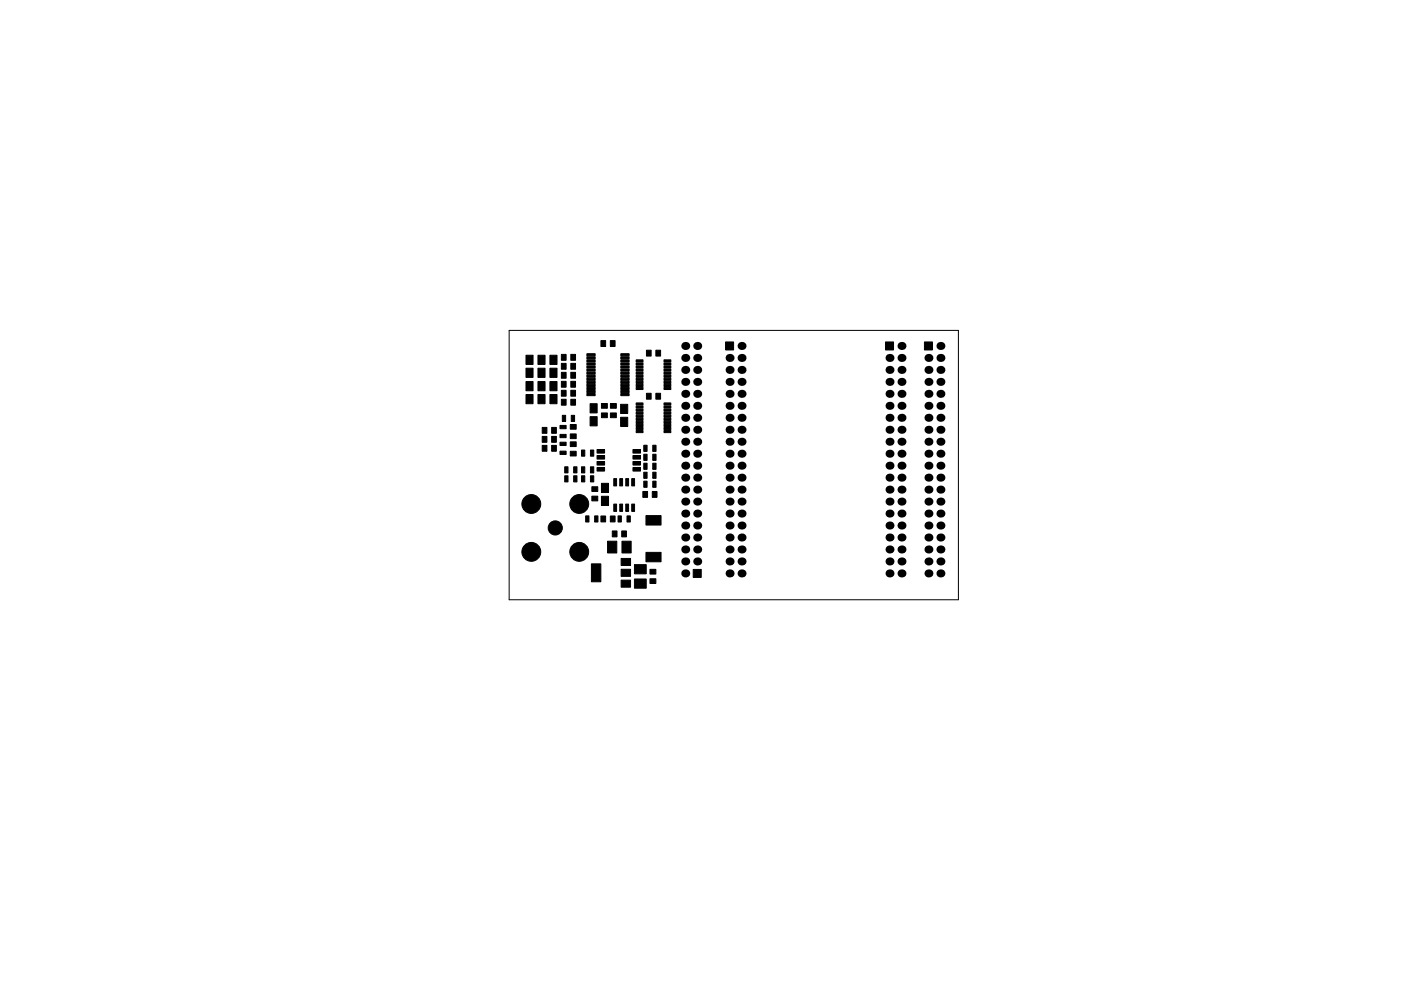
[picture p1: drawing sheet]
<svg xmlns="http://www.w3.org/2000/svg" width="297mm" height="210mm" viewBox="0 0 297 210" stroke-linecap="round" stroke-linejoin="round" font-family="sans-serif">
<path d="M107.9 70.1h95.3v57.1h-95.3z" fill="none" stroke="#000" stroke-width=".21"/>
<g fill="#000" stroke="#000" stroke-width=".21">
<path d="M111.5 75.4h1.5v1.9h-1.5zM111.5 78.1h1.5v2h-1.5zM114.1 75.4h1.5v1.9h-1.5zM114.1 78.1h1.5v2h-1.5zM116.6 75.4h1.5v1.9h-1.5zM116.6 78.1h1.5v2h-1.5zM119 79h1v1.2h-1zM119 77.1h1v1.2h-1zM119 75.2h1v1.2h-1zM121 79h1v1.2h-1zM121 77.1h1v1.2h-1zM121 75.2h1v1.2h-1z"/>
<path d="M124.4 75h1.8v.5h-1.8zM124.4 75.7h1.8v.4h-1.8zM124.4 76.3h1.8v.5h-1.8zM124.4 77h1.8v.4h-1.8zM124.4 77.6h1.8v.5h-1.8zM124.4 78.3h1.8v.4h-1.8zM124.4 78.9h1.8v.5h-1.8zM124.4 79.6h1.8v.4h-1.8zM127.4 72.3h1v1.2h-1zM129.4 72.3h1v1.2h-1zM131.6 79.6h1.8v.4h-1.8zM131.6 78.9h1.8v.5h-1.8z"/>
<path d="M131.6 78.3h1.8v.4h-1.8zM131.6 77.6h1.8v.5h-1.8zM131.6 77h1.8v.4h-1.8zM131.6 76.3h1.8v.5h-1.8zM131.6 75.7h1.8v.4h-1.8zM131.6 75h1.8v.5h-1.8zM134.9 76.3h1.4v.5h-1.4zM134.9 77h1.4v.4h-1.4zM134.9 77.6h1.4v.5h-1.4zM134.9 78.3h1.4v.4h-1.4zM134.9 78.9h1.4v.5h-1.4zM137.1 74.3h1v1.2h-1z"/>
<path d="M139.1 74.3h1v1.2h-1zM140.8 78.9h1.4v.5h-1.4zM140.8 78.3h1.4v.4h-1.4zM140.8 77.6h1.4v.5h-1.4zM140.8 77h1.4v.4h-1.4zM140.8 76.3h1.4v.5h-1.4zM153.8 72.6h1.7v1.7h-1.7zM187.7 72.6h1.7v1.7h-1.7zM196 72.6h1.7v1.7h-1.7zM111.5 81h1.5v1.9h-1.5zM111.5 83.7h1.5v2h-1.5zM114.1 81h1.5v1.9h-1.5z"/>
<path d="M114.1 83.7h1.5v2h-1.5zM115 94.5h1v1.2h-1zM115 92.6h1v1.2h-1zM115 90.7h1v1.2h-1zM116.6 81h1.5v1.9h-1.5zM116.6 83.7h1.5v2h-1.5zM117 94.5h1v1.2h-1zM117 92.6h1v1.2h-1zM117 90.7h1v1.2h-1zM118.7 93.8h1.3v.7h-1.3zM118.7 95.7h1.3v.7h-1.3zM118.7 90.3h1.3v.7h-1.3z"/>
<path d="M118.7 92.2h1.3v.7h-1.3zM119.2 88.1h.7v1.3h-.7zM119 84.7h1v1.3h-1zM119 80.9h1v1.3h-1zM119 82.8h1v1.3h-1zM119.7 99h.7v1.3h-.7zM121.1 88.1h.7v1.3h-.7zM121 84.7h1v1.3h-1zM121 80.9h1v1.3h-1zM121 82.8h1v1.3h-1zM120.9 95.7h1.3v1h-1.3zM120.9 93.7h1.3v1h-1.3z"/>
<path d="M120.9 92.1h1.3v1h-1.3zM120.9 90.1h1.3v1h-1.3zM121.6 99h.7v1.3h-.7zM123.3 95.5h.7v1.3h-.7zM125.1 85.7h1.5v1.9h-1.5zM125.1 88.4h1.5v2h-1.5zM125.2 95.5h.7v1.3h-.7zM124.4 80.2h1.8v.5h-1.8zM124.4 80.9h1.8v.4h-1.8zM124.4 81.5h1.8v.5h-1.8zM124.4 82.2h1.8v.4h-1.8zM124.4 82.8h1.8v.5h-1.8z"/>
<path d="M124.4 83.5h1.8v.4h-1.8zM127.5 85.6h1.3v1h-1.3zM127.5 87.6h1.3v1h-1.3zM126.6 95.4h1.6v.7h-1.6zM126.6 96.6h1.6v.8h-1.6zM126.6 97.9h1.6v.8h-1.6zM126.6 99.2h1.6v.7h-1.6zM129.4 85.6h1.3v1h-1.3zM129.4 87.6h1.3v1h-1.3zM131.6 85.8h1.5v1.9h-1.5zM131.6 88.5h1.5v2h-1.5zM131.6 83.5h1.8v.4h-1.8z"/>
<path d="M131.6 82.8h1.8v.5h-1.8zM131.6 82.2h1.8v.4h-1.8zM131.6 81.5h1.8v.5h-1.8zM131.6 80.9h1.8v.4h-1.8zM131.6 80.2h1.8v.5h-1.8zM134.9 79.6h1.4v.4h-1.4zM134.9 80.2h1.4v.5h-1.4zM134.9 80.9h1.4v.4h-1.4zM134.9 81.5h1.4v.5h-1.4zM134.9 82.2h1.4v.4h-1.4zM134.9 85.5h1.4v.4h-1.4zM134.9 86.1h1.4v.5h-1.4z"/>
<path d="M134.9 86.8h1.4v.4h-1.4zM134.9 87.4h1.4v.5h-1.4zM134.9 88.1h1.4v.4h-1.4zM134.9 88.7h1.4v.5h-1.4zM134.9 89.4h1.4v.4h-1.4zM134.9 90h1.4v.5h-1.4zM134.9 90.7h1.4v.4h-1.4zM134.9 91.3h1.4v.5h-1.4zM134.2 99.2h1.6v.7h-1.6zM134.2 97.9h1.6v.8h-1.6zM134.2 96.6h1.6v.8h-1.6zM134.2 95.4h1.6v.7h-1.6z"/>
<path d="M136.5 98.3h.7v1.3h-.7zM136.5 96.4h.7v1.3h-.7zM136.5 94.5h.7v1.3h-.7zM137.1 83.4h1v1.3h-1zM138.4 98.3h.7v1.3h-.7zM138.4 96.4h.7v1.3h-.7zM138.4 94.5h.7v1.3h-.7zM139.1 83.4h1v1.3h-1zM140.8 82.2h1.4v.4h-1.4zM140.8 81.5h1.4v.5h-1.4zM140.8 80.9h1.4v.4h-1.4zM140.8 80.2h1.4v.5h-1.4z"/>
<path d="M140.8 79.6h1.4v.4h-1.4zM140.8 91.3h1.4v.5h-1.4zM140.8 90.7h1.4v.4h-1.4zM140.8 90h1.4v.5h-1.4zM140.8 89.4h1.4v.4h-1.4zM140.8 88.7h1.4v.5h-1.4zM140.8 88.1h1.4v.4h-1.4zM140.8 87.4h1.4v.5h-1.4zM140.8 86.8h1.4v.4h-1.4zM140.8 86.1h1.4v.5h-1.4zM140.8 85.5h1.4v.4h-1.4zM119.7 100.9h.7v1.3h-.7z"/>
<path d="M121.6 100.9h.7v1.3h-.7zM123.3 99h.7v1.3h-.7zM123.3 100.9h.7v1.3h-.7zM124.2 109.5h.7v1.3h-.7zM125.2 99h.7v1.3h-.7zM125.5 103.3h1.2v1h-1.2zM125.5 105.3h1.2v1h-1.2zM125.2 100.9h.7v1.3h-.7zM126.1 109.5h.7v1.3h-.7zM125.4 119.6h2v3.8h-2zM127.5 102.5h1.5v2h-1.5zM127.5 105.3h1.5v1.9h-1.5z"/>
<path d="M127.4 109.5h1v1.2h-1zM129.4 109.5h1v1.2h-1zM130.1 106.9h.6v1.6h-.6zM130.1 101.5h.6v1.6h-.6zM128.8 114.8h2v2.5h-2zM129.8 112.7h1v1.2h-1zM131 109.5h.7v1.3h-.7zM131.4 106.9h.6v1.6h-.6zM131.4 101.5h.6v1.6h-.6zM131.8 112.7h1v1.2h-1zM132.9 109.5h.7v1.3h-.7zM132.7 106.9h.6v1.6h-.6z"/>
<path d="M132.7 101.5h.6v1.6h-.6zM131.7 118.5h2v1.5h-2zM131.9 114.8h1.9v2.5h-1.9zM134.5 119.8h2.5v1.9h-2.5zM133.9 106.9h.6v1.6h-.6zM133.9 101.5h.6v1.6h-.6zM136.3 104.3h1v1.2h-1zM136.5 102.1h.7v1.3h-.7zM136.5 100.2h.7v1.3h-.7zM138.3 104.3h1v1.2h-1zM138.4 102.1h.7v1.3h-.7zM138.4 100.2h.7v1.3h-.7z"/>
<path d="M137 117.2h3.2v2h-3.2zM137 109.4h3.2v2h-3.2zM131.7 120.8h2v1.5h-2zM131.7 123.1h2v1.5h-2zM134.5 122.8h2.5v2h-2.5zM137.8 120.8h1.3v1h-1.3zM137.8 122.8h1.3v1h-1.3zM147 120.8h1.7v1.7h-1.7z"/>
<circle cx="112.6" cy="106.9" r="2"/>
<circle cx="112.6" cy="117.1" r="2"/>
<circle cx="117.7" cy="112" r="1.5"/>
<circle cx="122.8" cy="106.9" r="2"/>
<circle cx="122.8" cy="117.1" r="2"/>
</g>
<g fill="#000">
<circle cx="145.3" cy="78.5" r=".85"/>
<circle cx="145.3" cy="75.9" r=".85"/>
<circle cx="145.3" cy="73.4" r=".85"/>
<circle cx="147.8" cy="78.5" r=".85"/>
<circle cx="147.8" cy="73.4" r=".85"/>
<circle cx="147.8" cy="75.9" r=".85"/>
<circle cx="154.7" cy="78.5" r=".85"/>
<circle cx="154.7" cy="75.9" r=".85"/>
<circle cx="157.2" cy="78.5" r=".85"/>
<circle cx="157.2" cy="73.4" r=".85"/>
<circle cx="157.2" cy="75.9" r=".85"/>
<circle cx="188.6" cy="78.5" r=".85"/>
<circle cx="188.6" cy="75.9" r=".85"/>
<circle cx="191.1" cy="78.5" r=".85"/>
<circle cx="191.1" cy="73.4" r=".85"/>
<circle cx="191.1" cy="75.9" r=".85"/>
<circle cx="196.8" cy="78.5" r=".85"/>
<circle cx="196.8" cy="75.9" r=".85"/>
<circle cx="199.4" cy="73.4" r=".85"/>
<circle cx="199.4" cy="78.5" r=".85"/>
<circle cx="199.4" cy="75.9" r=".85"/>
<circle cx="145.3" cy="96.3" r=".85"/>
<circle cx="145.3" cy="88.6" r=".85"/>
<circle cx="145.3" cy="83.6" r=".85"/>
<circle cx="145.3" cy="81" r=".85"/>
<circle cx="145.3" cy="93.7" r=".85"/>
<circle cx="145.3" cy="86.1" r=".85"/>
<circle cx="145.3" cy="98.8" r=".85"/>
<circle cx="145.3" cy="91.2" r=".85"/>
<circle cx="147.8" cy="93.7" r=".85"/>
<circle cx="147.8" cy="88.6" r=".85"/>
<circle cx="147.8" cy="86.1" r=".85"/>
<circle cx="147.8" cy="96.3" r=".85"/>
<circle cx="147.8" cy="91.2" r=".85"/>
<circle cx="147.8" cy="81" r=".85"/>
<circle cx="147.8" cy="98.8" r=".85"/>
<circle cx="147.8" cy="83.6" r=".85"/>
<circle cx="154.7" cy="93.7" r=".85"/>
<circle cx="154.7" cy="96.3" r=".85"/>
<circle cx="154.7" cy="81" r=".85"/>
<circle cx="154.7" cy="86.1" r=".85"/>
<circle cx="154.7" cy="83.6" r=".85"/>
<circle cx="154.7" cy="91.2" r=".85"/>
<circle cx="154.7" cy="98.8" r=".85"/>
<circle cx="154.7" cy="88.6" r=".85"/>
<circle cx="157.2" cy="96.3" r=".85"/>
<circle cx="157.2" cy="93.7" r=".85"/>
<circle cx="157.2" cy="86.1" r=".85"/>
<circle cx="157.2" cy="81" r=".85"/>
<circle cx="157.2" cy="83.6" r=".85"/>
<circle cx="157.2" cy="88.6" r=".85"/>
<circle cx="157.2" cy="91.2" r=".85"/>
<circle cx="157.2" cy="98.8" r=".85"/>
<circle cx="188.6" cy="96.3" r=".85"/>
<circle cx="188.6" cy="88.6" r=".85"/>
<circle cx="188.6" cy="86.1" r=".85"/>
<circle cx="188.6" cy="93.7" r=".85"/>
<circle cx="188.6" cy="83.6" r=".85"/>
<circle cx="188.6" cy="91.2" r=".85"/>
<circle cx="188.6" cy="81" r=".85"/>
<circle cx="188.6" cy="98.8" r=".85"/>
<circle cx="191.1" cy="86.1" r=".85"/>
<circle cx="191.1" cy="83.6" r=".85"/>
<circle cx="191.1" cy="88.6" r=".85"/>
<circle cx="191.1" cy="91.2" r=".85"/>
<circle cx="191.1" cy="93.7" r=".85"/>
<circle cx="191.1" cy="96.3" r=".85"/>
<circle cx="191.1" cy="81" r=".85"/>
<circle cx="191.1" cy="98.8" r=".85"/>
<circle cx="196.8" cy="91.2" r=".85"/>
<circle cx="196.8" cy="86.1" r=".85"/>
<circle cx="196.8" cy="88.6" r=".85"/>
<circle cx="196.8" cy="93.7" r=".85"/>
<circle cx="196.8" cy="81" r=".85"/>
<circle cx="196.8" cy="83.6" r=".85"/>
<circle cx="196.8" cy="96.3" r=".85"/>
<circle cx="196.8" cy="98.8" r=".85"/>
<circle cx="199.4" cy="88.6" r=".85"/>
<circle cx="199.4" cy="83.6" r=".85"/>
<circle cx="199.4" cy="86.1" r=".85"/>
<circle cx="199.4" cy="91.2" r=".85"/>
<circle cx="199.4" cy="93.7" r=".85"/>
<circle cx="199.4" cy="96.3" r=".85"/>
<circle cx="199.4" cy="81" r=".85"/>
<circle cx="199.4" cy="98.8" r=".85"/>
<circle cx="145.3" cy="114" r=".85"/>
<circle cx="145.3" cy="119.1" r=".85"/>
<circle cx="145.3" cy="116.6" r=".85"/>
<circle cx="145.3" cy="109" r=".85"/>
<circle cx="145.3" cy="101.3" r=".85"/>
<circle cx="145.3" cy="111.5" r=".85"/>
<circle cx="145.3" cy="103.9" r=".85"/>
<circle cx="145.3" cy="106.4" r=".85"/>
<circle cx="147.8" cy="109" r=".85"/>
<circle cx="147.8" cy="116.6" r=".85"/>
<circle cx="147.8" cy="103.9" r=".85"/>
<circle cx="147.8" cy="119.1" r=".85"/>
<circle cx="147.8" cy="114" r=".85"/>
<circle cx="147.8" cy="111.5" r=".85"/>
<circle cx="147.8" cy="101.3" r=".85"/>
<circle cx="147.8" cy="106.4" r=".85"/>
<circle cx="154.7" cy="103.9" r=".85"/>
<circle cx="154.7" cy="109" r=".85"/>
<circle cx="154.7" cy="116.6" r=".85"/>
<circle cx="154.7" cy="119.1" r=".85"/>
<circle cx="154.7" cy="111.5" r=".85"/>
<circle cx="154.7" cy="114" r=".85"/>
<circle cx="154.7" cy="101.3" r=".85"/>
<circle cx="154.7" cy="106.4" r=".85"/>
<circle cx="157.2" cy="114" r=".85"/>
<circle cx="157.2" cy="119.1" r=".85"/>
<circle cx="157.2" cy="106.4" r=".85"/>
<circle cx="157.2" cy="111.5" r=".85"/>
<circle cx="157.2" cy="116.6" r=".85"/>
<circle cx="157.2" cy="101.3" r=".85"/>
<circle cx="157.2" cy="109" r=".85"/>
<circle cx="157.2" cy="103.9" r=".85"/>
<circle cx="188.6" cy="109" r=".85"/>
<circle cx="188.6" cy="116.6" r=".85"/>
<circle cx="188.6" cy="101.3" r=".85"/>
<circle cx="188.6" cy="103.9" r=".85"/>
<circle cx="188.6" cy="106.4" r=".85"/>
<circle cx="188.6" cy="111.5" r=".85"/>
<circle cx="188.6" cy="119.1" r=".85"/>
<circle cx="188.6" cy="114" r=".85"/>
<circle cx="191.1" cy="111.5" r=".85"/>
<circle cx="191.1" cy="109" r=".85"/>
<circle cx="191.1" cy="116.6" r=".85"/>
<circle cx="191.1" cy="101.3" r=".85"/>
<circle cx="191.1" cy="103.9" r=".85"/>
<circle cx="191.1" cy="106.4" r=".85"/>
<circle cx="191.1" cy="119.1" r=".85"/>
<circle cx="191.1" cy="114" r=".85"/>
<circle cx="196.8" cy="101.3" r=".85"/>
<circle cx="196.8" cy="109" r=".85"/>
<circle cx="196.8" cy="116.6" r=".85"/>
<circle cx="196.8" cy="103.9" r=".85"/>
<circle cx="196.8" cy="106.4" r=".85"/>
<circle cx="196.8" cy="111.5" r=".85"/>
<circle cx="196.8" cy="119.1" r=".85"/>
<circle cx="196.8" cy="114" r=".85"/>
<circle cx="199.4" cy="116.6" r=".85"/>
<circle cx="199.4" cy="101.3" r=".85"/>
<circle cx="199.4" cy="103.9" r=".85"/>
<circle cx="199.4" cy="106.4" r=".85"/>
<circle cx="199.4" cy="109" r=".85"/>
<circle cx="199.4" cy="114" r=".85"/>
<circle cx="199.4" cy="111.5" r=".85"/>
<circle cx="199.4" cy="119.1" r=".85"/>
<circle cx="145.3" cy="121.7" r=".85"/>
<circle cx="154.7" cy="121.7" r=".85"/>
<circle cx="157.2" cy="121.7" r=".85"/>
<circle cx="188.6" cy="121.7" r=".85"/>
<circle cx="191.1" cy="121.7" r=".85"/>
<circle cx="196.8" cy="121.7" r=".85"/>
<circle cx="199.4" cy="121.7" r=".85"/>
</g>
</svg>
